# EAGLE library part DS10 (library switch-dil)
DIL/CODE SWITCH

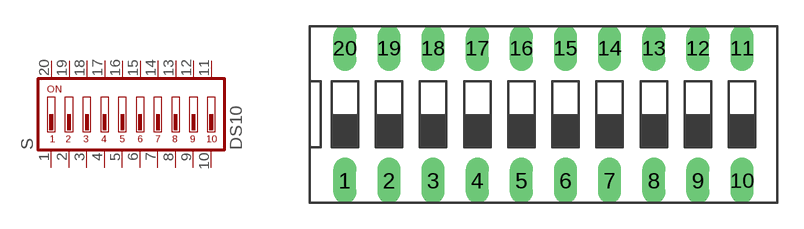
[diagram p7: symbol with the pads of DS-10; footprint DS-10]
Designator prefix S

## DS10 (OC_FARNELL: unknown; OC_NEWARK: unknown)  [DS-10]
1  1  pas
2  2  pas
3  3  pas
4  4  pas
5  5  pas
6  6  pas
7  7  pas
8  8  pas
9  9  pas
10  10  pas
11  11  pas
12  12  pas
13  13  pas
14  14  pas
15  15  pas
16  16  pas
17  17  pas
18  18  pas
19  19  pas
20  20  pas

## Footprint DS-10 (pad centres in mm)
DIL/CODE SWITCH Mors distributor Buerklin, 17G566
drill 0.813 long: 1 -11.43,-3.81; 2 -8.89,-3.81; 3 -6.35,-3.81; 4 -3.81,-3.81; 5 -1.27,-3.81; 6 1.27,-3.81; 7 3.81,-3.81; 8 6.35,-3.81; 9 8.89,-3.81; 10 11.43,-3.81; 11 11.43,3.81; 12 8.89,3.81; 13 6.35,3.81; 14 3.81,3.81; 15 1.27,3.81; 16 -1.27,3.81; 17 -3.81,3.81; 18 -6.35,3.81; 19 -8.89,3.81; 20 -11.43,3.81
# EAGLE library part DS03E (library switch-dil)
DIL/CODE SWITCH

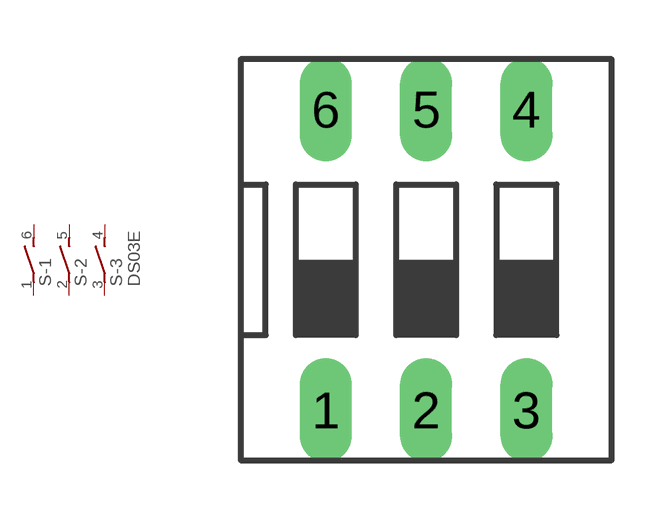
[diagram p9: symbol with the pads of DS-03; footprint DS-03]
Designator prefix S; gates -1=S -2=S -3=S+V

## DS03E (OC_FARNELL: 1255223; OC_NEWARK: unknown)  [DS-03]
1  -1:1  pas
2  -2:1  pas
3  -3:1  pas
4  -3:2  pas
5  -2:2  pas
6  -1:2  pas

## Footprint DS-03 (pad centres in mm)
DIL/CODE SWITCH Mors distributor Buerklin, 17G552
drill 0.813 long: 1 -2.54,-3.81; 2 0,-3.81; 3 2.54,-3.81; 4 2.54,3.81; 5 0,3.81; 6 -2.54,3.81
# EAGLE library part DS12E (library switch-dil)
DIL/CODE SWITCH

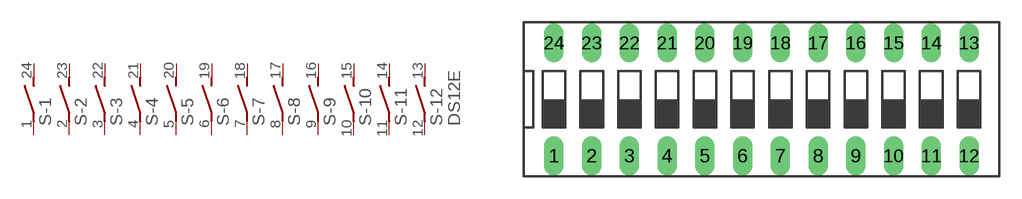
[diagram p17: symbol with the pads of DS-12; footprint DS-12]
Designator prefix S; gates -1=S -2=S -3=S -4=S -5=S -6=S -7=S -8=S -9=S -10=S -11=S -12=S+V

## DS12E (OC_FARNELL: unknown; OC_NEWARK: unknown)  [DS-12]
1  -1:1  pas
2  -2:1  pas
3  -3:1  pas
4  -4:1  pas
5  -5:1  pas
6  -6:1  pas
7  -7:1  pas
8  -8:1  pas
9  -9:1  pas
10  -10:1  pas
11  -11:1  pas
12  -12:1  pas
13  -12:2  pas
14  -11:2  pas
15  -10:2  pas
16  -9:2  pas
17  -8:2  pas
18  -7:2  pas
19  -6:2  pas
20  -5:2  pas
21  -4:2  pas
22  -3:2  pas
23  -2:2  pas
24  -1:2  pas

## Footprint DS-12 (pad centres in mm)
DIL/CODE SWITCH Mors distributor Buerklin, 17G568
drill 0.813 long: 1 -13.97,-3.81; 2 -11.43,-3.81; 3 -8.89,-3.81; 4 -6.35,-3.81; 5 -3.81,-3.81; 6 -1.27,-3.81; 7 1.27,-3.81; 8 3.81,-3.81; 9 6.35,-3.81; 10 8.89,-3.81; 11 11.43,-3.81; 12 13.97,-3.81; 13 13.97,3.81; 14 11.43,3.81; 15 8.89,3.81; 16 6.35,3.81; 17 3.81,3.81; 18 1.27,3.81; 19 -1.27,3.81; 20 -3.81,3.81; 21 -6.35,3.81; 22 -8.89,3.81; 23 -11.43,3.81; 24 -13.97,3.81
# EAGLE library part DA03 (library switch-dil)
DIL/CODE SWITCH

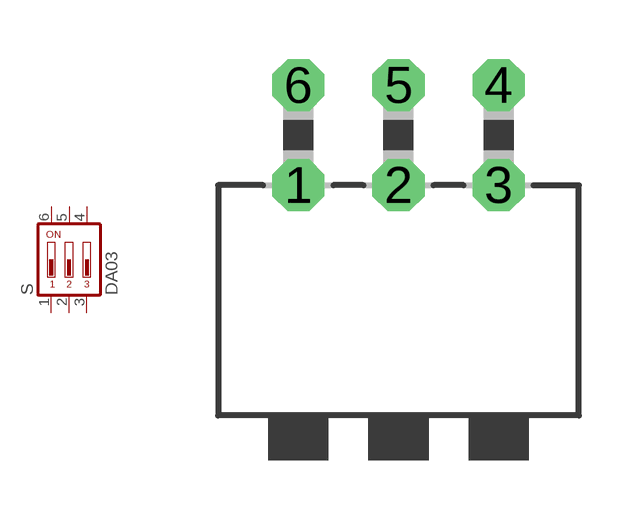
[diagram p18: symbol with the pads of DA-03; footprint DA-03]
Designator prefix S

## DA03 (MPN: MCDA03; OC_FARNELL: 1521999; OC_NEWARK: 74M2972)  [DA-03]
1  1  pas
2  2  pas
3  3  pas
4  4  pas
5  5  pas
6  6  pas

## Footprint DA-03 (pad centres in mm)
DIL/CODE SWITCH Mors
drill 0.813 octagon: 1 -2.54,-1.27; 2 0,-1.27; 3 2.54,-1.27; 4 2.54,1.27; 5 0,1.27; 6 -2.54,1.27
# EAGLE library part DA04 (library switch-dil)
DIL/CODE SWITCH

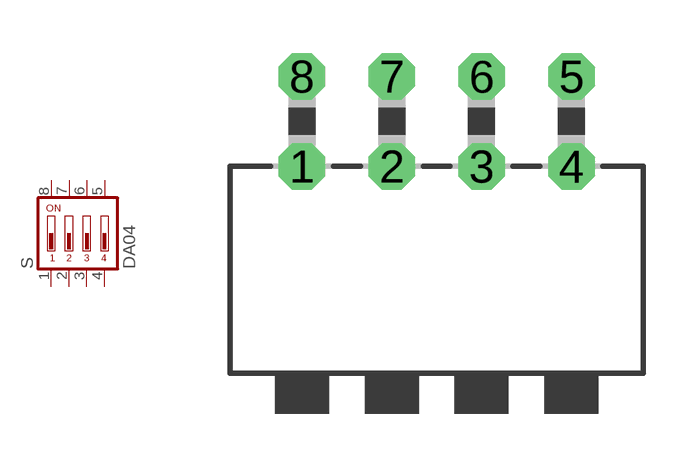
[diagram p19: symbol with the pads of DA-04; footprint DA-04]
Designator prefix S

## DA04 (MPN: MCDA04; OC_FARNELL: 9471545; OC_NEWARK: 26M1090)  [DA-04]
1  1  pas
2  2  pas
3  3  pas
4  4  pas
5  5  pas
6  6  pas
7  7  pas
8  8  pas

## Footprint DA-04 (pad centres in mm)
DIL/CODE SWITCH Mors distributor Buerklin, 17G584
drill 0.813 octagon: 1 -3.81,-1.27; 2 -1.27,-1.27; 3 1.27,-1.27; 4 3.81,-1.27; 5 3.81,1.27; 6 1.27,1.27; 7 -1.27,1.27; 8 -3.81,1.27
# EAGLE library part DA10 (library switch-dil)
DIL/CODE SWITCH

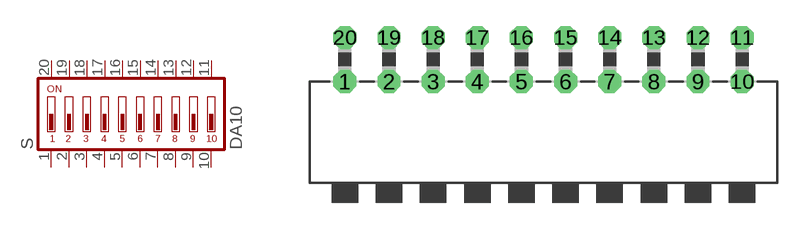
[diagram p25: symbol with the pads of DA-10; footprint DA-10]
Designator prefix S

## DA10 (OC_FARNELL: unknown; OC_NEWARK: unknown)  [DA-10]
1  1  pas
2  2  pas
3  3  pas
4  4  pas
5  5  pas
6  6  pas
7  7  pas
8  8  pas
9  9  pas
10  10  pas
11  11  pas
12  12  pas
13  13  pas
14  14  pas
15  15  pas
16  16  pas
17  17  pas
18  18  pas
19  19  pas
20  20  pas

## Footprint DA-10 (pad centres in mm)
DIL/CODE SWITCH Mors
drill 0.813 octagon: 1 -11.43,-1.27; 2 -8.89,-1.27; 3 -6.35,-1.27; 4 -3.81,-1.27; 5 -1.27,-1.27; 6 1.27,-1.27; 7 3.81,-1.27; 8 6.35,-1.27; 9 8.89,-1.27; 10 11.43,-1.27; 11 11.43,1.27; 12 8.89,1.27; 13 6.35,1.27; 14 3.81,1.27; 15 1.27,1.27; 16 -1.27,1.27; 17 -3.81,1.27; 18 -6.35,1.27; 19 -8.89,1.27; 20 -11.43,1.27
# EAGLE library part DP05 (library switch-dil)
DIL/CODE SWITCH

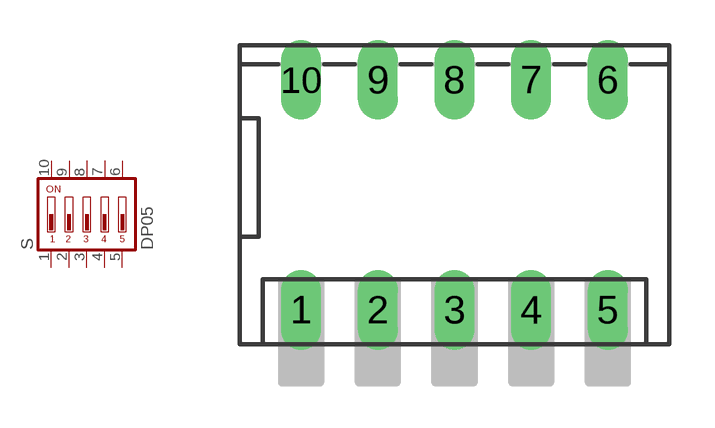
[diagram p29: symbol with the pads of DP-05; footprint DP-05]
Designator prefix S

## DP05 (MPN: DP05; OC_FARNELL: 1522005; OC_NEWARK: 73J0029)  [DP-05]
1  1  pas
2  2  pas
3  3  pas
4  4  pas
5  5  pas
6  6  pas
7  7  pas
8  8  pas
9  9  pas
10  10  pas

## Footprint DP-05 (pad centres in mm)
DIL/CODE SWITCH
drill 0.813 long: 1 -5.08,-3.81; 2 -2.54,-3.81; 3 0,-3.81; 4 2.54,-3.81; 5 5.08,-3.81; 6 5.08,3.81; 7 2.54,3.81; 8 0,3.81; 9 -2.54,3.81; 10 -5.08,3.81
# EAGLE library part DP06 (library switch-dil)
DIL/CODE SWITCH

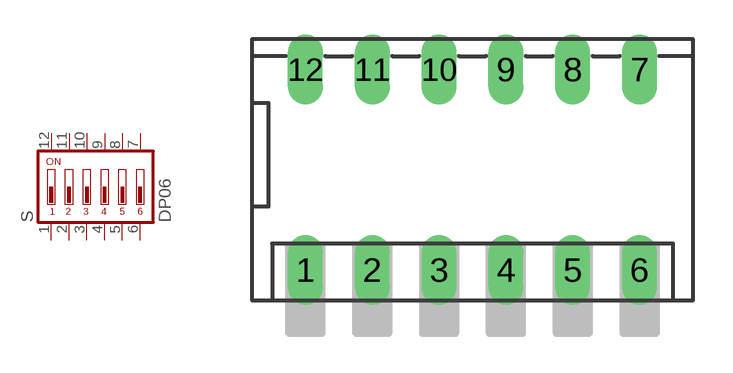
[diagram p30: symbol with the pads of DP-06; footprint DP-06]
Designator prefix S

## DP06 (MPN: MCDP06; OC_FARNELL: 9471618; OC_NEWARK: 26M1097)  [DP-06]
1  1  pas
2  2  pas
3  3  pas
4  4  pas
5  5  pas
6  6  pas
7  7  pas
8  8  pas
9  9  pas
10  10  pas
11  11  pas
12  12  pas

## Footprint DP-06 (pad centres in mm)
DIL/CODE SWITCH distributor Buerklin, 17G572
drill 0.813 long: 1 -6.35,-3.81; 2 -3.81,-3.81; 3 -1.27,-3.81; 4 1.27,-3.81; 5 3.81,-3.81; 6 6.35,-3.81; 7 6.35,3.81; 8 3.81,3.81; 9 1.27,3.81; 10 -1.27,3.81; 11 -3.81,3.81; 12 -6.35,3.81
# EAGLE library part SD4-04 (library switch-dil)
DIL/CODE SWITCH

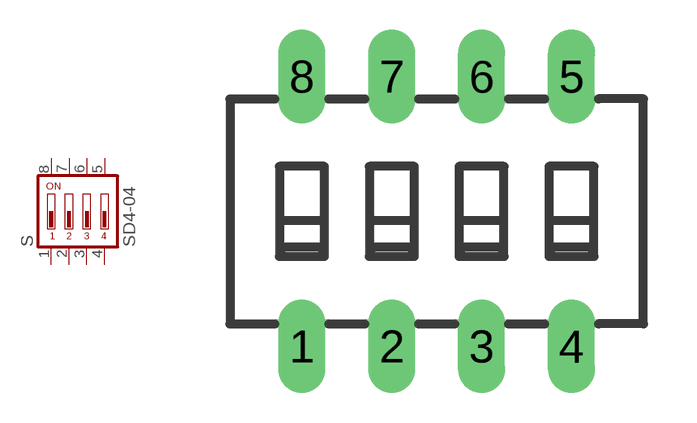
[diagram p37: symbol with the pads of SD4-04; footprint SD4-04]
Designator prefix S

## SD4-04 (OC_FARNELL: unknown; OC_NEWARK: unknown)  [SD4-04]
1  1  pas
2  2  pas
3  3  pas
4  4  pas
5  5  pas
6  6  pas
7  7  pas
8  8  pas

## Footprint SD4-04 (pad centres in mm)
DIL/CODE SWITCH Mors
drill 0.813 long: 1 -3.81,-3.81; 2 -1.27,-3.81; 3 1.27,-3.81; 4 3.81,-3.81; 5 3.81,3.81; 6 1.27,3.81; 7 -1.27,3.81; 8 -3.81,3.81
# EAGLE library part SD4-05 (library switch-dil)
DIL/CODE SWITCH

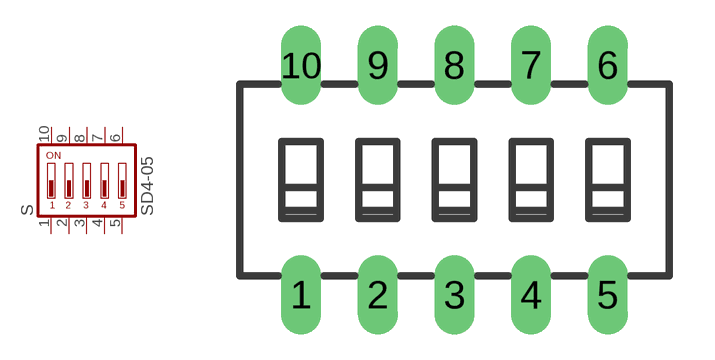
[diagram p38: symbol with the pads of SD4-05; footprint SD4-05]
Designator prefix S

## SD4-05 (OC_FARNELL: unknown; OC_NEWARK: unknown)  [SD4-05]
1  1  pas
2  2  pas
3  3  pas
4  4  pas
5  5  pas
6  6  pas
7  7  pas
8  8  pas
9  9  pas
10  10  pas

## Footprint SD4-05 (pad centres in mm)
DIL/CODE SWITCH Mors
drill 0.813 long: 1 -5.08,-3.81; 2 -2.54,-3.81; 3 0,-3.81; 4 2.54,-3.81; 5 5.08,-3.81; 6 5.08,3.81; 7 2.54,3.81; 8 0,3.81; 9 -2.54,3.81; 10 -5.08,3.81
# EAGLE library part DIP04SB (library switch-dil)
DIL/CODE SWITCH

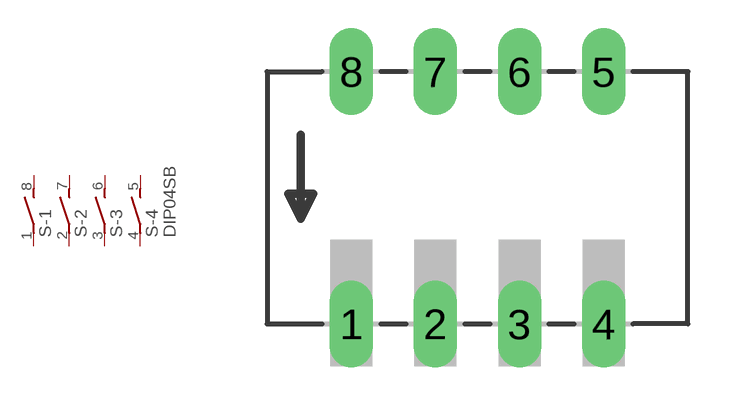
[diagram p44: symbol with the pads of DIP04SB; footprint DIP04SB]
Designator prefix S; gates -1=S -2=S -3=S -4=S+V

## DIP04SB (OC_FARNELL: unknown; OC_NEWARK: unknown)  [DIP04SB]
1  -1:1  pas
2  -2:1  pas
3  -3:1  pas
4  -4:1  pas
5  -4:2  pas
6  -3:2  pas
7  -2:2  pas
8  -1:2  pas

## Footprint DIP04SB (pad centres in mm)
DIL/CODE SWITCH
drill 0.813 long: 1 -3.81,-3.81; 2 -1.27,-3.81; 3 1.27,-3.81; 4 3.81,-3.81; 5 3.81,3.81; 6 1.27,3.81; 7 -1.27,3.81; 8 -3.81,3.81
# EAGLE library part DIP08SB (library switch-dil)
DIL/CODE SWITCH

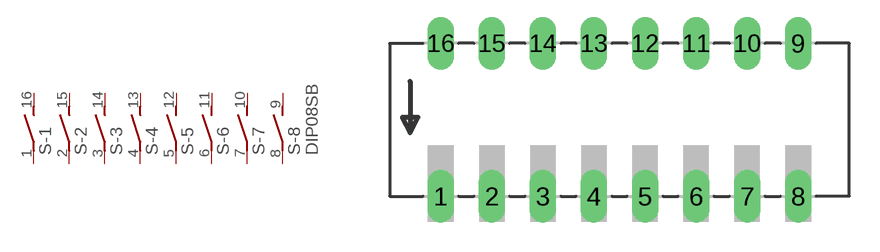
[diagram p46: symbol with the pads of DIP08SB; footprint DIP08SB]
Designator prefix S; gates -1=S -2=S -3=S -4=S -5=S -6=S -7=S -8=S+V

## DIP08SB (OC_FARNELL: unknown; OC_NEWARK: unknown)  [DIP08SB]
1  -1:1  pas
2  -2:1  pas
3  -3:1  pas
4  -4:1  pas
5  -5:1  pas
6  -6:1  pas
7  -7:1  pas
8  -8:1  pas
9  -8:2  pas
10  -7:2  pas
11  -6:2  pas
12  -5:2  pas
13  -4:2  pas
14  -3:2  pas
15  -2:2  pas
16  -1:2  pas

## Footprint DIP08SB (pad centres in mm)
DIL/CODE SWITCH
drill 0.813 long: 1 -8.89,-3.81; 2 -6.35,-3.81; 3 -3.81,-3.81; 4 -1.27,-3.81; 5 1.27,-3.81; 6 3.81,-3.81; 7 6.35,-3.81; 8 8.89,-3.81; 9 8.89,3.81; 10 6.35,3.81; 11 3.81,3.81; 12 1.27,3.81; 13 -1.27,3.81; 14 -3.81,3.81; 15 -6.35,3.81; 16 -8.89,3.81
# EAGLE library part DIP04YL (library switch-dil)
DIL/CODE SWITCH

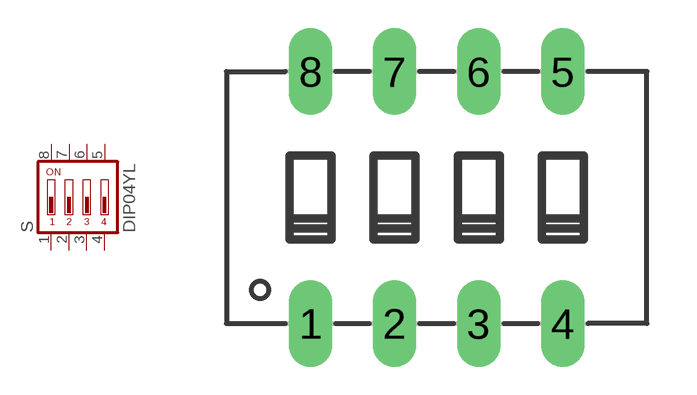
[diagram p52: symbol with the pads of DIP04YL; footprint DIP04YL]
Designator prefix S

## DIP04YL (OC_FARNELL: unknown; OC_NEWARK: unknown)  [DIP04YL]
1  1  pas
2  2  pas
3  3  pas
4  4  pas
5  5  pas
6  6  pas
7  7  pas
8  8  pas

## Footprint DIP04YL (pad centres in mm)
DIL/CODE SWITCH
drill 0.813 long: 1 -3.81,-3.81; 2 -1.27,-3.81; 3 1.27,-3.81; 4 3.81,-3.81; 5 3.81,3.81; 6 1.27,3.81; 7 -1.27,3.81; 8 -3.81,3.81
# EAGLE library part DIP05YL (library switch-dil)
DIL/CODE SWITCH

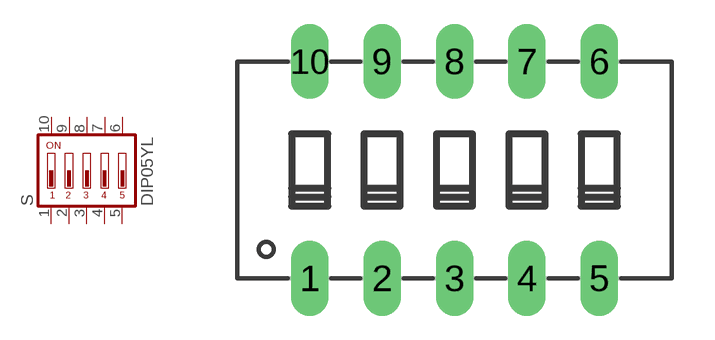
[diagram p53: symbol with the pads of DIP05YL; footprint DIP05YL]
Designator prefix S

## DIP05YL (OC_FARNELL: unknown; OC_NEWARK: unknown)  [DIP05YL]
1  1  pas
2  2  pas
3  3  pas
4  4  pas
5  5  pas
6  6  pas
7  7  pas
8  8  pas
9  9  pas
10  10  pas

## Footprint DIP05YL (pad centres in mm)
DIL/CODE SWITCH
drill 0.813 long: 1 -5.08,-3.81; 2 -2.54,-3.81; 3 0,-3.81; 4 2.54,-3.81; 5 5.08,-3.81; 6 5.08,3.81; 7 2.54,3.81; 8 0,3.81; 9 -2.54,3.81; 10 -5.08,3.81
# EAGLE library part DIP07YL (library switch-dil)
DIL/CODE SWITCH

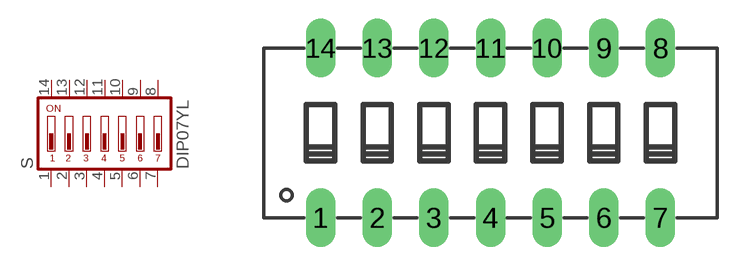
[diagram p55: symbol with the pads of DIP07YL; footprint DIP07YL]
Designator prefix S

## DIP07YL (OC_FARNELL: unknown; OC_NEWARK: unknown)  [DIP07YL]
1  1  pas
2  2  pas
3  3  pas
4  4  pas
5  5  pas
6  6  pas
7  7  pas
8  8  pas
9  9  pas
10  10  pas
11  11  pas
12  12  pas
13  13  pas
14  14  pas

## Footprint DIP07YL (pad centres in mm)
DIL/CODE SWITCH
drill 0.813 long: 1 -7.62,-3.81; 2 -5.08,-3.81; 3 -2.54,-3.81; 4 0,-3.81; 5 2.54,-3.81; 6 5.08,-3.81; 7 7.62,-3.81; 8 7.62,3.81; 9 5.08,3.81; 10 2.54,3.81; 11 0,3.81; 12 -2.54,3.81; 13 -5.08,3.81; 14 -7.62,3.81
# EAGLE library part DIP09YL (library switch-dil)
DIL/CODE SWITCH

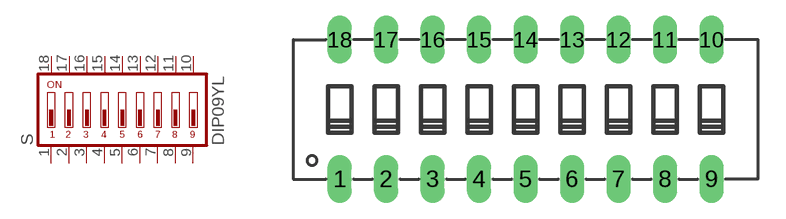
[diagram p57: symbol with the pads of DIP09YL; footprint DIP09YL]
Designator prefix S

## DIP09YL (OC_FARNELL: unknown; OC_NEWARK: unknown)  [DIP09YL]
1  1  pas
2  2  pas
3  3  pas
4  4  pas
5  5  pas
6  6  pas
7  7  pas
8  8  pas
9  9  pas
10  10  pas
11  11  pas
12  12  pas
13  13  pas
14  14  pas
15  15  pas
16  16  pas
17  17  pas
18  18  pas

## Footprint DIP09YL (pad centres in mm)
DIL/CODE SWITCH
drill 0.813 long: 1 -10.16,-3.81; 2 -7.62,-3.81; 3 -5.08,-3.81; 4 -2.54,-3.81; 5 0,-3.81; 6 2.54,-3.81; 7 5.08,-3.81; 8 7.62,-3.81; 9 10.16,-3.81; 10 10.16,3.81; 11 7.62,3.81; 12 5.08,3.81; 13 2.54,3.81; 14 0,3.81; 15 -2.54,3.81; 16 -5.08,3.81; 17 -7.62,3.81; 18 -10.16,3.81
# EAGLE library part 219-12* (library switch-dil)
Surface Mount DIP Switch Series 219 SMT CTS Electronic Components Sourc: www.ctscorp.com

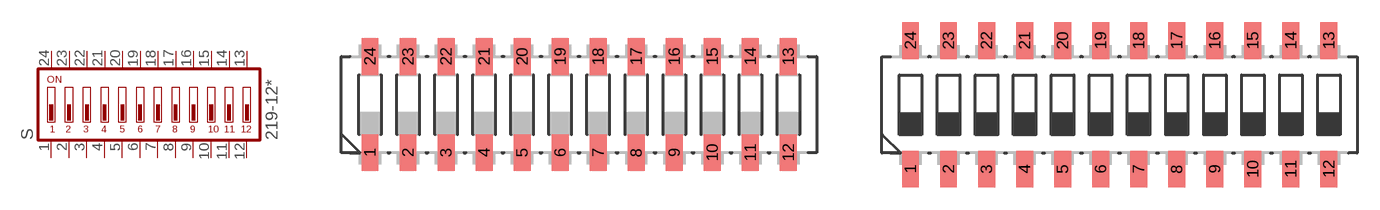
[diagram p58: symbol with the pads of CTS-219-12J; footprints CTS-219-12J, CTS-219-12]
Designator prefix S

## 219-12J (OC_FARNELL: unknown; OC_NEWARK: unknown)  [CTS-219-12J]
1  1  pas
2  2  pas
3  3  pas
4  4  pas
5  5  pas
6  6  pas
7  7  pas
8  8  pas
9  9  pas
10  10  pas
11  11  pas
12  12  pas
13  13  pas
14  14  pas
15  15  pas
16  16  pas
17  17  pas
18  18  pas
19  19  pas
20  20  pas
21  21  pas
22  22  pas
23  23  pas
24  24  pas

## 219-12 (OC_FARNELL: unknown; OC_NEWARK: unknown)  [CTS-219-12]
Pads as for CTS-219-12J

## Footprint CTS-219-12J (pad centres in mm)
Surface Mount DIP Switch Series 219 SMT "J" Bend CTS Electronic Components Sourc: www.ctscorp.com
smd 1.13 x 2.44: 1 -13.97,-3.215; 2 -11.43,-3.215; 3 -8.89,-3.215; 4 -6.35,-3.215; 5 -3.81,-3.215; 6 -1.27,-3.215; 7 1.27,-3.215; 8 3.81,-3.215; 9 6.35,-3.215; 10 8.89,-3.215; 11 11.43,-3.215; 12 13.97,-3.215; 13 13.97,3.215; 14 11.43,3.215; 15 8.89,3.215; 16 6.35,3.215; 17 3.81,3.215; 18 1.27,3.215; 19 -1.27,3.215; 20 -3.81,3.215; 21 -6.35,3.215; 22 -8.89,3.215; 23 -11.43,3.215; 24 -13.97,3.215

## Footprint CTS-219-12 (pad centres in mm)
Surface Mount DIP Switch Series 219 SMT CTS Electronic Components Sourc: www.ctscorp.com
smd 1.13 x 2.44: 1 -13.97,-4.3; 2 -11.43,-4.3; 3 -8.89,-4.3; 4 -6.35,-4.3; 5 -3.81,-4.3; 6 -1.27,-4.3; 7 1.27,-4.3; 8 3.81,-4.3; 9 6.35,-4.3; 10 8.89,-4.3; 11 11.43,-4.3; 12 13.97,-4.3; 13 13.97,4.3; 14 11.43,4.3; 15 8.89,4.3; 16 6.35,4.3; 17 3.81,4.3; 18 1.27,4.3; 19 -1.27,4.3; 20 -3.81,4.3; 21 -6.35,4.3; 22 -8.89,4.3; 23 -11.43,4.3; 24 -13.97,4.3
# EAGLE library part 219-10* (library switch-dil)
Surface Mount DIP Switch Series 219 SMT CTS Electronic Components Sourc: www.ctscorp.com

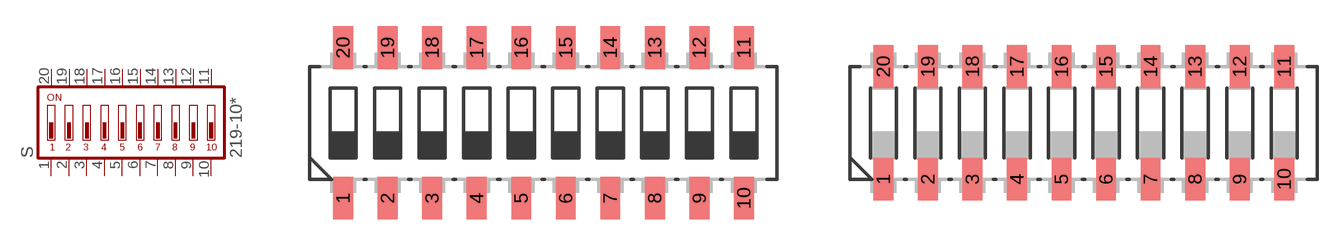
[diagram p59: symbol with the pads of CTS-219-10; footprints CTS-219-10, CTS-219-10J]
Designator prefix S

## 219-10 (MF: SLI (CML/IDI); MPN: 219-10PK; OC_FARNELL: unknown; OC_NEWARK: 19M0224)  [CTS-219-10]
1  1  pas
2  2  pas
3  3  pas
4  4  pas
5  5  pas
6  6  pas
7  7  pas
8  8  pas
9  9  pas
10  10  pas
11  11  pas
12  12  pas
13  13  pas
14  14  pas
15  15  pas
16  16  pas
17  17  pas
18  18  pas
19  19  pas
20  20  pas

## 219-10J (OC_FARNELL: unknown; OC_NEWARK: unknown)  [CTS-219-10J]
Pads as for CTS-219-10

## Footprint CTS-219-10 (pad centres in mm)
Surface Mount DIP Switch Series 219 SMT CTS Electronic Components Sourc: www.ctscorp.com
smd 1.13 x 2.44: 1 -11.43,-4.3; 2 -8.89,-4.3; 3 -6.35,-4.3; 4 -3.81,-4.3; 5 -1.27,-4.3; 6 1.27,-4.3; 7 3.81,-4.3; 8 6.35,-4.3; 9 8.89,-4.3; 10 11.43,-4.3; 11 11.43,4.3; 12 8.89,4.3; 13 6.35,4.3; 14 3.81,4.3; 15 1.27,4.3; 16 -1.27,4.3; 17 -3.81,4.3; 18 -6.35,4.3; 19 -8.89,4.3; 20 -11.43,4.3

## Footprint CTS-219-10J (pad centres in mm)
Surface Mount DIP Switch Series 219 SMT "J" Bend CTS Electronic Components Sourc: www.ctscorp.com
smd 1.13 x 2.44: 1 -11.43,-3.215; 2 -8.89,-3.215; 3 -6.35,-3.215; 4 -3.81,-3.215; 5 -1.27,-3.215; 6 1.27,-3.215; 7 3.81,-3.215; 8 6.35,-3.215; 9 8.89,-3.215; 10 11.43,-3.215; 11 11.43,3.215; 12 8.89,3.215; 13 6.35,3.215; 14 3.81,3.215; 15 1.27,3.215; 16 -1.27,3.215; 17 -3.81,3.215; 18 -6.35,3.215; 19 -8.89,3.215; 20 -11.43,3.215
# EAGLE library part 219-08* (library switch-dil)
Surface Mount DIP Switch Series 219 SMT CTS Electronic Components Sourc: www.ctscorp.com

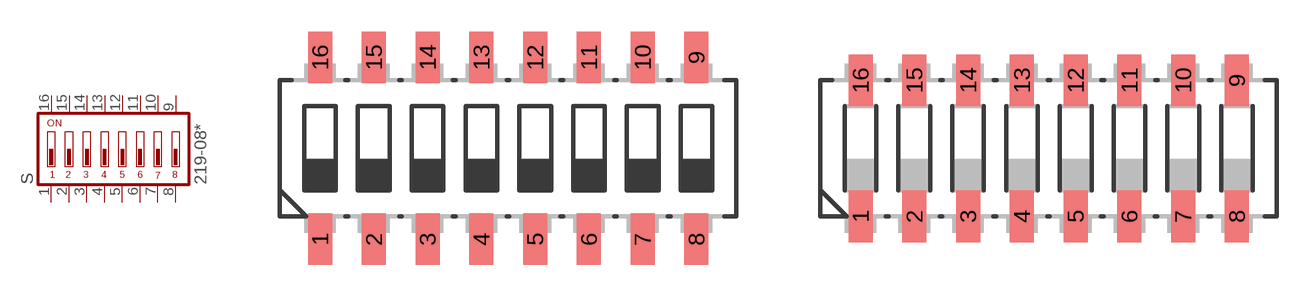
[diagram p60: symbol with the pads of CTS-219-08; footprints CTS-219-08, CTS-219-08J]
Designator prefix S

## 219-08 (OC_FARNELL: unknown; OC_NEWARK: unknown)  [CTS-219-08]
1  1  pas
2  2  pas
3  3  pas
4  4  pas
5  5  pas
6  6  pas
7  7  pas
8  8  pas
9  9  pas
10  10  pas
11  11  pas
12  12  pas
13  13  pas
14  14  pas
15  15  pas
16  16  pas

## 219-08J (OC_FARNELL: unknown; OC_NEWARK: unknown)  [CTS-219-08J]
Pads as for CTS-219-08

## Footprint CTS-219-08 (pad centres in mm)
Surface Mount DIP Switch Series 219 SMT CTS Electronic Components Sourc: www.ctscorp.com
smd 1.13 x 2.44: 1 -8.89,-4.3; 2 -6.35,-4.3; 3 -3.81,-4.3; 4 -1.27,-4.3; 5 1.27,-4.3; 6 3.81,-4.3; 7 6.35,-4.3; 8 8.89,-4.3; 9 8.89,4.3; 10 6.35,4.3; 11 3.81,4.3; 12 1.27,4.3; 13 -1.27,4.3; 14 -3.81,4.3; 15 -6.35,4.3; 16 -8.89,4.3

## Footprint CTS-219-08J (pad centres in mm)
Surface Mount DIP Switch Series 219 SMT "J" Bend CTS Electronic Components Sourc: www.ctscorp.com
smd 1.13 x 2.44: 1 -8.89,-3.215; 2 -6.35,-3.215; 3 -3.81,-3.215; 4 -1.27,-3.215; 5 1.27,-3.215; 6 3.81,-3.215; 7 6.35,-3.215; 8 8.89,-3.215; 9 8.89,3.215; 10 6.35,3.215; 11 3.81,3.215; 12 1.27,3.215; 13 -1.27,3.215; 14 -3.81,3.215; 15 -6.35,3.215; 16 -8.89,3.215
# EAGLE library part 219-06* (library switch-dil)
Surface Mount DIP Switch Series 219 SMT CTS Electronic Components Sourc: www.ctscorp.com

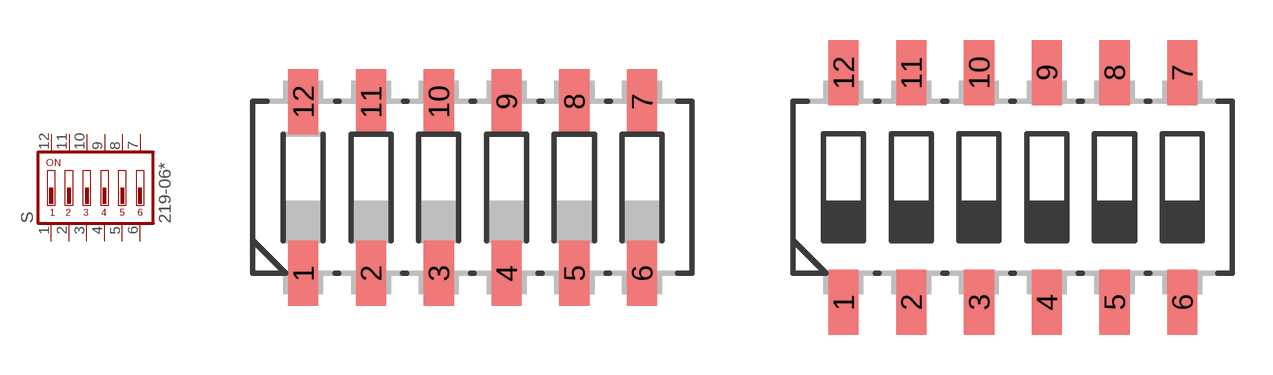
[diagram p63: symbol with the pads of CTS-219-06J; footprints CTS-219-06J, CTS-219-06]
Designator prefix S

## 219-06J (OC_FARNELL: unknown; OC_NEWARK: unknown)  [CTS-219-06J]
1  1  pas
2  2  pas
3  3  pas
4  4  pas
5  5  pas
6  6  pas
7  7  pas
8  8  pas
9  9  pas
10  10  pas
11  11  pas
12  12  pas

## 219-06 (OC_FARNELL: unknown; OC_NEWARK: unknown)  [CTS-219-06]
Pads as for CTS-219-06J

## Footprint CTS-219-06J (pad centres in mm)
Surface Mount DIP Switch Series 219 SMT "J" Bend CTS Electronic Components Sourc: www.ctscorp.com
smd 1.13 x 2.44: 1 -6.35,-3.215; 2 -3.81,-3.215; 3 -1.27,-3.215; 4 1.27,-3.215; 5 3.81,-3.215; 6 6.35,-3.215; 7 6.35,3.215; 8 3.81,3.215; 9 1.27,3.215; 10 -1.27,3.215; 11 -3.81,3.215; 12 -6.35,3.215

## Footprint CTS-219-06 (pad centres in mm)
Surface Mount DIP Switch Series 219 SMT CTS Electronic Components Sourc: www.ctscorp.com
smd 1.13 x 2.44: 1 -6.35,-4.3; 2 -3.81,-4.3; 3 -1.27,-4.3; 4 1.27,-4.3; 5 3.81,-4.3; 6 6.35,-4.3; 7 6.35,4.3; 8 3.81,4.3; 9 1.27,4.3; 10 -1.27,4.3; 11 -3.81,4.3; 12 -6.35,4.3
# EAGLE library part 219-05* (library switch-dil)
Surface Mount DIP Switch Series 219 SMT CTS Electronic Components Sourc: www.ctscorp.com

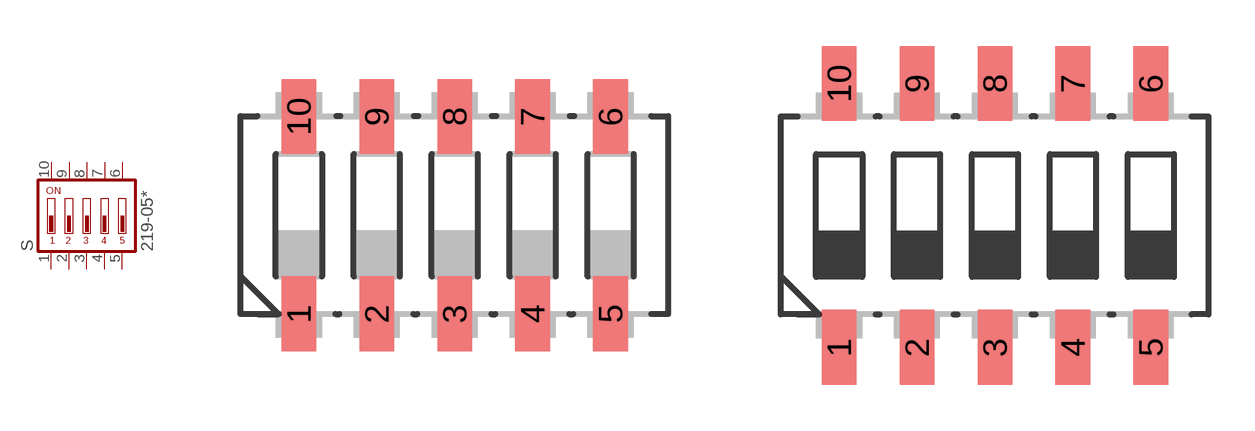
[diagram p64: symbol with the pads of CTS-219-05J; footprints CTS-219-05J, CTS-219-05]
Designator prefix S

## 219-05J (OC_FARNELL: unknown; OC_NEWARK: unknown)  [CTS-219-05J]
1  1  pas
2  2  pas
3  3  pas
4  4  pas
5  5  pas
6  6  pas
7  7  pas
8  8  pas
9  9  pas
10  10  pas

## 219-05 (OC_FARNELL: unknown; OC_NEWARK: unknown)  [CTS-219-05]
Pads as for CTS-219-05J

## Footprint CTS-219-05J (pad centres in mm)
Surface Mount DIP Switch Series 219 SMT "J" Bend CTS Electronic Components Sourc: www.ctscorp.com
smd 1.13 x 2.44: 1 -5.08,-3.215; 2 -2.54,-3.215; 3 0,-3.215; 4 2.54,-3.215; 5 5.08,-3.215; 6 5.08,3.215; 7 2.54,3.215; 8 0,3.215; 9 -2.54,3.215; 10 -5.08,3.215

## Footprint CTS-219-05 (pad centres in mm)
Surface Mount DIP Switch Series 219 SMT CTS Electronic Components Sourc: www.ctscorp.com
smd 1.13 x 2.44: 1 -5.08,-4.3; 2 -2.54,-4.3; 3 0,-4.3; 4 2.54,-4.3; 5 5.08,-4.3; 6 5.08,4.3; 7 2.54,4.3; 8 0,4.3; 9 -2.54,4.3; 10 -5.08,4.3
